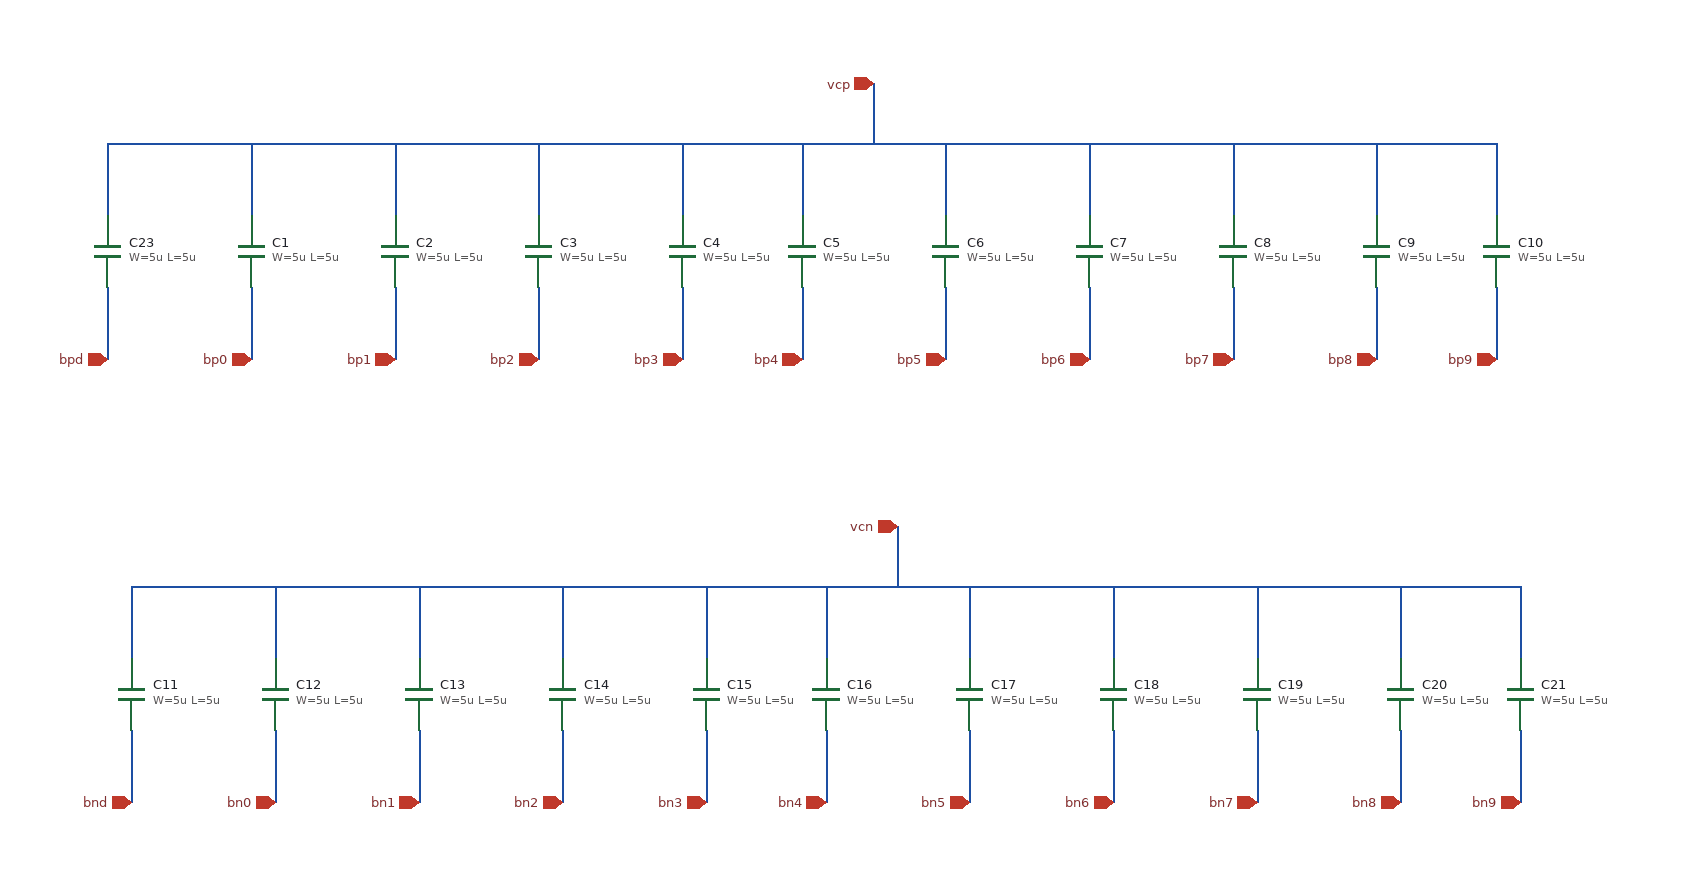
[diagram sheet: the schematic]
v {xschem version=3.4.5 file_version=1.2
}
G {}
K {}
V {}
S {}
E {}
N 80 -800 80 -740 {
lab=vcp}
N 80 -800 1240 -800 {
lab=vcp}
N 1240 -800 1240 -740 {
lab=vcp}
N 1140 -800 1140 -740 {
lab=vcp}
N 1020 -800 1020 -740 {
lab=vcp}
N 900 -800 900 -740 {
lab=vcp}
N 780 -800 780 -740 {
lab=vcp}
N 660 -800 660 -740 {
lab=vcp}
N 560 -800 560 -740 {
lab=vcp}
N 440 -800 440 -740 {
lab=vcp}
N 320 -800 320 -740 {
lab=vcp}
N 200 -800 200 -740 {
lab=vcp}
N 80 -680 80 -620 {
lab=bpd}
N 200 -680 200 -620 {
lab=bp0}
N 320 -680 320 -620 {
lab=bp1}
N 440 -680 440 -620 {
lab=bp2}
N 560 -680 560 -620 {
lab=bp3}
N 660 -680 660 -620 {
lab=bp4}
N 780 -680 780 -620 {
lab=bp5}
N 900 -680 900 -620 {
lab=bp6}
N 1020 -680 1020 -620 {
lab=bp7}
N 1140 -680 1140 -620 {
lab=bp8}
N 1240 -680 1240 -620 {
lab=bp9}
N 720 -850 720 -800 {
lab=vcp}
N 100 -430 100 -370 {
lab=vcn}
N 100 -430 1260 -430 {
lab=vcn}
N 1260 -430 1260 -370 {
lab=vcn}
N 1160 -430 1160 -370 {
lab=vcn}
N 1040 -430 1040 -370 {
lab=vcn}
N 920 -430 920 -370 {
lab=vcn}
N 800 -430 800 -370 {
lab=vcn}
N 680 -430 680 -370 {
lab=vcn}
N 580 -430 580 -370 {
lab=vcn}
N 460 -430 460 -370 {
lab=vcn}
N 340 -430 340 -370 {
lab=vcn}
N 220 -430 220 -370 {
lab=vcn}
N 100 -310 100 -250 {
lab=bnd}
N 220 -310 220 -250 {
lab=bn0}
N 340 -310 340 -250 {
lab=bn1}
N 460 -310 460 -250 {
lab=bn2}
N 580 -310 580 -250 {
lab=bn3}
N 680 -310 680 -250 {
lab=bn4}
N 800 -310 800 -250 {
lab=bn5}
N 920 -310 920 -250 {
lab=bn6}
N 1040 -310 1040 -250 {
lab=bn7}
N 1160 -310 1160 -250 {
lab=bn8}
N 1260 -310 1260 -250 {
lab=bn9}
N 740 -480 740 -430 {
lab=vcn}
C {iopin.sym} 720 -850 3 0 {name=p11 lab=vcp}
C {iopin.sym} 740 -480 3 0 {name=p18 lab=vcn}
C {iopin.sym} 80 -620 1 0 {name=p1 lab=bpd}
C {iopin.sym} 200 -620 1 0 {name=p2 lab=bp0}
C {iopin.sym} 320 -620 1 0 {name=p3 lab=bp1}
C {iopin.sym} 440 -620 1 0 {name=p4 lab=bp2}
C {iopin.sym} 560 -620 1 0 {name=p5 lab=bp3}
C {iopin.sym} 660 -620 1 0 {name=p6 lab=bp4}
C {iopin.sym} 780 -620 1 0 {name=p7 lab=bp5}
C {iopin.sym} 900 -620 1 0 {name=p8 lab=bp6}
C {iopin.sym} 1020 -620 1 0 {name=p9 lab=bp7}
C {iopin.sym} 1140 -620 1 0 {name=p10 lab=bp8}
C {iopin.sym} 1240 -620 1 0 {name=p12 lab=bp9}
C {iopin.sym} 100 -250 1 0 {name=p13 lab=bnd}
C {iopin.sym} 340 -250 1 0 {name=p14 lab=bn1}
C {iopin.sym} 460 -250 1 0 {name=p15 lab=bn2}
C {iopin.sym} 580 -250 1 0 {name=p16 lab=bn3}
C {iopin.sym} 680 -250 1 0 {name=p17 lab=bn4}
C {iopin.sym} 800 -250 1 0 {name=p19 lab=bn5}
C {iopin.sym} 920 -250 1 0 {name=p20 lab=bn6}
C {iopin.sym} 1040 -250 1 0 {name=p21 lab=bn7}
C {iopin.sym} 1160 -250 1 0 {name=p22 lab=bn8}
C {iopin.sym} 1260 -250 1 0 {name=p23 lab=bn9}
C {iopin.sym} 220 -250 1 0 {name=p24 lab=bn0}
C {symbols/cap_mim_2f0fF.sym} 80 -710 0 0 {name=C23
W=5u
L=5u
model=cap_mim_2f0fF
spiceprefix=X
m=1}
C {symbols/cap_mim_2f0fF.sym} 200 -710 0 0 {name=C1
W=5u
L=5u
model=cap_mim_2f0fF
spiceprefix=X
m=1}
C {symbols/cap_mim_2f0fF.sym} 320 -710 0 0 {name=C2
W=5u
L=5u
model=cap_mim_2f0fF
spiceprefix=X
m=2}
C {symbols/cap_mim_2f0fF.sym} 440 -710 0 0 {name=C3
W=5u
L=5u
model=cap_mim_2f0fF
spiceprefix=X
m=4}
C {symbols/cap_mim_2f0fF.sym} 560 -710 0 0 {name=C4
W=5u
L=5u
model=cap_mim_2f0fF
spiceprefix=X
m=8}
C {symbols/cap_mim_2f0fF.sym} 660 -710 0 0 {name=C5
W=5u
L=5u
model=cap_mim_2f0fF
spiceprefix=X
m=16}
C {symbols/cap_mim_2f0fF.sym} 780 -710 0 0 {name=C6
W=5u
L=5u
model=cap_mim_2f0fF
spiceprefix=X
m=32}
C {symbols/cap_mim_2f0fF.sym} 900 -710 0 0 {name=C7
W=5u
L=5u
model=cap_mim_2f0fF
spiceprefix=X
m=64}
C {symbols/cap_mim_2f0fF.sym} 1020 -710 0 0 {name=C8
W=5u
L=5u
model=cap_mim_2f0fF
spiceprefix=X
m=128}
C {symbols/cap_mim_2f0fF.sym} 1140 -710 0 0 {name=C9
W=5u
L=5u
model=cap_mim_2f0fF
spiceprefix=X
m=256}
C {symbols/cap_mim_2f0fF.sym} 1240 -710 0 0 {name=C10
W=5u
L=5u
model=cap_mim_2f0fF
spiceprefix=X
m=512}
C {symbols/cap_mim_2f0fF.sym} 100 -340 0 0 {name=C11
W=5u
L=5u
model=cap_mim_2f0fF
spiceprefix=X
m=1}
C {symbols/cap_mim_2f0fF.sym} 220 -340 0 0 {name=C12
W=5u
L=5u
model=cap_mim_2f0fF
spiceprefix=X
m=1}
C {symbols/cap_mim_2f0fF.sym} 340 -340 0 0 {name=C13
W=5u
L=5u
model=cap_mim_2f0fF
spiceprefix=X
m=2}
C {symbols/cap_mim_2f0fF.sym} 460 -340 0 0 {name=C14
W=5u
L=5u
model=cap_mim_2f0fF
spiceprefix=X
m=4}
C {symbols/cap_mim_2f0fF.sym} 580 -340 0 0 {name=C15
W=5u
L=5u
model=cap_mim_2f0fF
spiceprefix=X
m=8}
C {symbols/cap_mim_2f0fF.sym} 680 -340 0 0 {name=C16
W=5u
L=5u
model=cap_mim_2f0fF
spiceprefix=X
m=16}
C {symbols/cap_mim_2f0fF.sym} 800 -340 0 0 {name=C17
W=5u
L=5u
model=cap_mim_2f0fF
spiceprefix=X
m=32}
C {symbols/cap_mim_2f0fF.sym} 920 -340 0 0 {name=C18
W=5u
L=5u
model=cap_mim_2f0fF
spiceprefix=X
m=64}
C {symbols/cap_mim_2f0fF.sym} 1040 -340 0 0 {name=C19
W=5u
L=5u
model=cap_mim_2f0fF
spiceprefix=X
m=128}
C {symbols/cap_mim_2f0fF.sym} 1160 -340 0 0 {name=C20
W=5u
L=5u
model=cap_mim_2f0fF
spiceprefix=X
m=256}
C {symbols/cap_mim_2f0fF.sym} 1260 -340 0 0 {name=C21
W=5u
L=5u
model=cap_mim_2f0fF
spiceprefix=X
m=512}
C {title.sym} 160 0 0 0 {name=l1 author="Arjun Ananth"}
